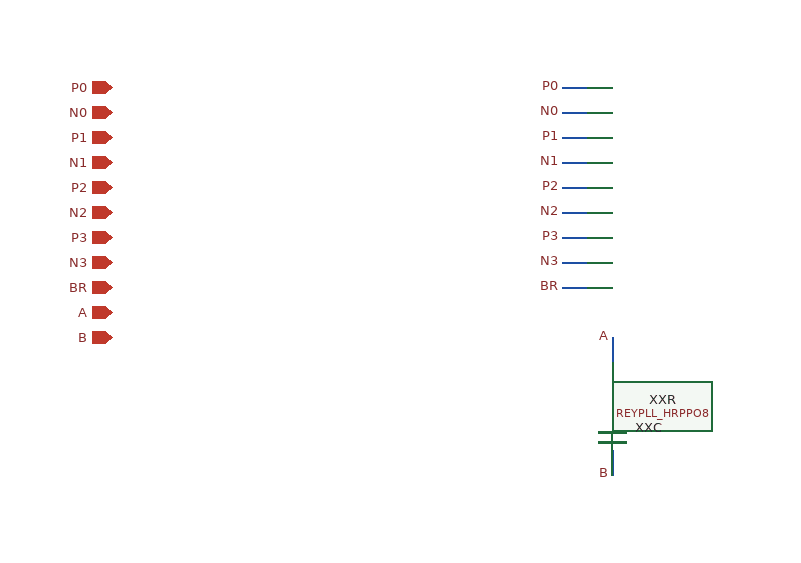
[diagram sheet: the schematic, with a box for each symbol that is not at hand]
v {xschem version=3.0.0 file_version=1.2 }
G {}
K {}
V {}
S {}
E {}
C {devices/iopin.sym} 0 0 0 0 {name=p0 lab=P0}
C {devices/iopin.sym} 0 20 0 0 {name=p1 lab=N0}
C {devices/iopin.sym} 0 40 0 0 {name=p2 lab=P1}
C {devices/iopin.sym} 0 60 0 0 {name=p3 lab=N1}
C {devices/iopin.sym} 0 80 0 0 {name=p4 lab=P2}
C {devices/iopin.sym} 0 100 0 0 {name=p5 lab=N2}
C {devices/iopin.sym} 0 120 0 0 {name=p6 lab=P3}
C {devices/iopin.sym} 0 140 0 0 {name=p7 lab=N3}
C {devices/iopin.sym} 0 160 0 0 {name=p8 lab=BR}
C {devices/iopin.sym} 0 180 0 0 {name=p9 lab=A}
C {devices/iopin.sym} 0 200 0 0 {name=p10 lab=B}
C {REY_PLL_SKY130A/REYPLL_HRPPO8.sym} 400 0 0 0 {name=XXR}
N 360.0 0.0 380.0 0.0 {lab=P0}
C {devices/lab_pin.sym} 360.0 0.0 0 0 {name=l0 sig_type=std_logic lab=P0 }
N 360.0 20.0 380.0 20.0 {lab=N0}
C {devices/lab_pin.sym} 360.0 20.0 0 0 {name=l1 sig_type=std_logic lab=N0 }
N 360.0 40.0 380.0 40.0 {lab=P1}
C {devices/lab_pin.sym} 360.0 40.0 0 0 {name=l2 sig_type=std_logic lab=P1 }
N 360.0 60.0 380.0 60.0 {lab=N1}
C {devices/lab_pin.sym} 360.0 60.0 0 0 {name=l3 sig_type=std_logic lab=N1 }
N 360.0 80.0 380.0 80.0 {lab=P2}
C {devices/lab_pin.sym} 360.0 80.0 0 0 {name=l4 sig_type=std_logic lab=P2 }
N 360.0 100.0 380.0 100.0 {lab=N2}
C {devices/lab_pin.sym} 360.0 100.0 0 0 {name=l5 sig_type=std_logic lab=N2 }
N 360.0 120.0 380.0 120.0 {lab=P3}
C {devices/lab_pin.sym} 360.0 120.0 0 0 {name=l6 sig_type=std_logic lab=P3 }
N 360.0 140.0 380.0 140.0 {lab=N3}
C {devices/lab_pin.sym} 360.0 140.0 0 0 {name=l7 sig_type=std_logic lab=N3 }
N 360.0 160.0 380.0 160.0 {lab=BR}
C {devices/lab_pin.sym} 360.0 160.0 0 0 {name=l8 sig_type=std_logic lab=BR }
C {REY_PLL_SKY130A/REYPLL_MIMU16.sym} 400 280 0 0 {name=XXC}
N 400.0 200.0 400.0 220.0 {lab=A}
C {devices/lab_pin.sym} 400.0 200.0 3 0 {name=l9 sig_type=std_logic lab=A }
N 400.0 310.0 400.0 290.0 {lab=B}
C {devices/lab_pin.sym} 400.0 310.0 1 0 {name=l10 sig_type=std_logic lab=B }
